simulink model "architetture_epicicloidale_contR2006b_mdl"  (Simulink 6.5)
settings: Solver=ode45  StartTime=0.0  StopTime=3  RelTol=1e-3
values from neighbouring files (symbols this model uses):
  al = Tipo(2)    [Flusso_Rotorico_An.m]
  b_c = kb*J_c    (= 4.94590955184)    [architetture_epicicloidale.m]    (also in architetture_epicicloidale_cont.m; architetture_epicicloidale_HEV.m = 92.8974810391; architetture_epicicloidale_prova.m; architetture_HEV_controllo.m = 9.28974810391)
  b_r = kb*J_r    (= 218.026030555)    [architetture_epicicloidale.m]    (also in architetture_epicicloidale_cont.m; architetture_epicicloidale_HEV.m; architetture_epicicloidale_prova.m; architetture_HEV_controllo.m = 21.8026030555)
  b_s = kb*J_s    (= 8.12277148259)    [architetture_epicicloidale.m]    (also in architetture_epicicloidale_cont.m; architetture_epicicloidale_HEV.m = 4.94590955184; architetture_epicicloidale_prova.m; architetture_HEV_controllo.m = 0.494590955184)
  b_sc = kb*J_sc    (= 92.8974810391)    [architetture_epicicloidale.m]    (also in architetture_epicicloidale_cont.m; architetture_epicicloidale_prova.m; epicicloidale.m; epicicloidale_da_solo.m)
  bm = 0.8*N*metri*secondo/rad    (= 0.8)    [architetture_epicicloidale.m]    (also in architetture_epicicloidale_cont.m; architetture_epicicloidale_HEV.m; architetture_epicicloidale_prova.m; architetture_HEV_controllo.m)
  d_cs = d0    (= 10)    [architetture_epicicloidale.m]    (also in architetture_epicicloidale_cont.m; architetture_epicicloidale_prova.m; epicicloidale.m; epicicloidale_da_solo.m)
  d_sr = d0    (= 10)    [architetture_epicicloidale.m]    (also in architetture_epicicloidale_cont.m; architetture_epicicloidale_prova.m; epicicloidale.m; epicicloidale_da_solo.m)
  I_m = eye(m-1)    [architetture_epicicloidale.m]    (also in architetture_epicicloidale_cont.m; architetture_epicicloidale_HEV.m; architetture_epicicloidale_prova.m; architetture_HEV_controllo.m)
  Iw0 = 0*wI0    [architetture_epicicloidale.m]    (also in architetture_epicicloidale_cont.m = wI0; architetture_epicicloidale_HEV.m; architetture_epicicloidale_prova.m; architetture_HEV_controllo.m)
  J_c = 1.3*0.5*pi*rho_acc*hc*r_c^4    (= 0.0494590955184)    [architetture_epicicloidale.m]    (also in architetture_epicicloidale_cont.m; architetture_epicicloidale_HEV.m = 0.928974810391; architetture_epicicloidale_prova.m; architetture_HEV_controllo.m = 0.928974810391)
  J_r = 0.5*pi*rho_acc*(hr*r_ri^4 + h_ring*(r_re^4-r_ri^4))    (= 2.18026030555)    [architetture_epicicloidale.m]    (also in architetture_epicicloidale_cont.m; architetture_epicicloidale_HEV.m; architetture_epicicloidale_prova.m; architetture_HEV_controllo.m)
  J_s = Nr_sat*0.5*pi*rho_acc*(hs*r_s^4 + hc*r_s^4)    (= 0.0812277148259)    [architetture_epicicloidale.m]    (also in architetture_epicicloidale_cont.m; architetture_epicicloidale_HEV.m = 0.0494590955184; architetture_epicicloidale_prova.m; architetture_HEV_controllo.m = 0.0494590955184)
  J_sc = Nr_sat*(r_c+r_s)^2*rho_acc*pi*(hs*r_s^2 + hc*r_s^2)    (= 0.928974810391)    [architetture_epicicloidale.m]    (also in architetture_epicicloidale_cont.m; architetture_epicicloidale_prova.m; epicicloidale.m; epicicloidale_da_solo.m)
  Jm = 1.6*kg*metri^2    (= 1.6)    [architetture_epicicloidale.m]    (also in architetture_epicicloidale_cont.m; architetture_epicicloidale_HEV.m = 1.64945909552; architetture_epicicloidale_prova.m; architetture_HEV_controllo.m = 0.529459095518)
  Jr = Jr([1:m-1],[1:m-1])    [architetture_epicicloidale.m]    (also in architetture_epicicloidale_cont.m; architetture_epicicloidale_HEV.m; architetture_epicicloidale_prova.m; architetture_HEV_controllo.m)
  K_cs = K0    (= 10000000)    [architetture_epicicloidale.m]    (also in architetture_epicicloidale_cont.m; architetture_epicicloidale_prova.m; epicicloidale.m; epicicloidale_da_solo.m)
  K_sr = K0    (= 10000000)    [architetture_epicicloidale.m]    (also in architetture_epicicloidale_cont.m; architetture_epicicloidale_prova.m; epicicloidale.m; epicicloidale_da_solo.m)
  Kf = diag(diag(MLb)'./fliplr(tau_m(1:m-1)))    [architetture_epicicloidale_cont.m]    (also in architetture_epicicloidale_HEV.m; architetture_epicicloidale_prova.m; architetture_HEV_controllo.m; architetture_HEV_startstop.m)
  Kr = Kr([1:m-1])    [architetture_epicicloidale.m]    (also in architetture_epicicloidale_cont.m; architetture_epicicloidale_HEV.m; architetture_epicicloidale_prova.m; architetture_HEV_controllo.m)
  Li = 0.1*Henry    (= 0.1)    [architetture_epicicloidale.m]    (also in architetture_epicicloidale_cont.m; architetture_epicicloidale_HEV.m; architetture_epicicloidale_prova.m; architetture_HEV_controllo.m)
  m = 5    [architetture_epicicloidale.m]    (also in architetture_epicicloidale_cont.m; architetture_epicicloidale_HEV.m; architetture_epicicloidale_prova.m; architetture_HEV_controllo.m)
  Mi = 0.08*Henry    (= 0.08)    [architetture_epicicloidale.m]    (also in architetture_epicicloidale_cont.m; architetture_epicicloidale_HEV.m; architetture_epicicloidale_prova.m; architetture_HEV_controllo.m)
  MKr = MKr([1:m-1],[1:m-1])    [architetture_epicicloidale.m]    (also in architetture_epicicloidale_cont.m; architetture_epicicloidale_HEV.m; architetture_epicicloidale_prova.m; architetture_HEV_controllo.m)
  MLb = MLb([1:m-1],[1:m-1])    [architetture_epicicloidale.m]    (also in architetture_epicicloidale_cont.m; architetture_epicicloidale_HEV.m; architetture_epicicloidale_prova.m; architetture_HEV_controllo.m)
  MR = MR([1:m-1],[1:m-1])    [architetture_epicicloidale.m]    (also in architetture_epicicloidale_cont.m; architetture_epicicloidale_HEV.m; architetture_epicicloidale_prova.m; architetture_HEV_controllo.m)
  Nar = 200    [architetture_epicicloidale.m]    (also in architetture_epicicloidale_cont.m; architetture_epicicloidale_HEV.m; architetture_epicicloidale_prova.m; architetture_HEV_controllo.m)
  Nc = 30    [architetture_epicicloidale.m]    (also in architetture_epicicloidale_cont.m; architetture_epicicloidale_HEV.m; architetture_epicicloidale_prova.m; architetture_HEV_controllo.m)
  Nr_sat = 4    [architetture_epicicloidale.m]    (also in architetture_epicicloidale_cont.m; architetture_epicicloidale_HEV.m; architetture_epicicloidale_prova.m; architetture_HEV_controllo.m)
  p = 1    [architetture_epicicloidale.m]    (also in architetture_epicicloidale_cont.m; architetture_epicicloidale_HEV.m; architetture_epicicloidale_prova.m; architetture_HEV_controllo.m)
  Phir = 0.02*Weber    (= 0.02)    [architetture_epicicloidale.m]    (also in architetture_epicicloidale_cont.m; architetture_epicicloidale_HEV.m; architetture_epicicloidale_prova.m; architetture_HEV_controllo.m)
  r_c = r_ri-2*r_s    (= 0.101859163579)    [architetture_epicicloidale.m]    (also in architetture_epicicloidale_cont.m; architetture_epicicloidale_prova.m; epicicloidale.m; epicicloidale_da_solo.m)
  r_ri = xds*Nr/(2*pi)    (= 0.248281711223)    [architetture_epicicloidale.m]    (also in architetture_epicicloidale_cont.m; architetture_epicicloidale_prova.m; epicicloidale.m; epicicloidale_da_solo.m)
  r_s = xds*Ns/(2*pi)    (= 0.0732112738223)    [architetture_epicicloidale.m]    (also in architetture_epicicloidale_cont.m; architetture_epicicloidale_HEV.m = 0.101859163579; architetture_epicicloidale_prova.m; architetture_HEV_controllo.m = 0.101859163579)
  Ri = 3*Ohm    (= 3)    [architetture_epicicloidale.m]    (also in architetture_epicicloidale_cont.m; architetture_epicicloidale_HEV.m; architetture_epicicloidale_prova.m; architetture_HEV_controllo.m = 0.1)
  Star = Si    [architetture_epicicloidale.m]    (also in architetture_epicicloidale_cont.m; architetture_epicicloidale_HEV.m; architetture_epicicloidale_prova.m; architetture_HEV_controllo.m)
  Tau_sc = 200*N*metri    (= 200)    [architetture_epicicloidale.m]    (also in architetture_epicicloidale_cont.m = 50; architetture_epicicloidale_prova.m = 50; epicicloidale.m = 4; epicicloidale_da_solo.m = 4)
  Tc = 0.05*ms    (= 5e-05)    [architetture_epicicloidale.m]    (also in architetture_epicicloidale_cont.m; architetture_epicicloidale_HEV.m; architetture_epicicloidale_prova.m; architetture_HEV_controllo.m)
  Thm0 = 0    [architetture_epicicloidale.m]    (also in architetture_epicicloidale_cont.m; architetture_epicicloidale_HEV.m; architetture_epicicloidale_prova.m; architetture_HEV_controllo.m)
  Tipo = eval(Flusso(ij).Tipo)    [architetture_epicicloidale.m]    (also in architetture_epicicloidale_cont.m; architetture_epicicloidale_HEV.m; architetture_epicicloidale_prova.m; architetture_HEV_controllo.m)
  tTb = tTb(:,[1:m-1])    [architetture_epicicloidale.m]    (also in architetture_epicicloidale_cont.m; architetture_epicicloidale_HEV.m; architetture_epicicloidale_prova.m; architetture_HEV_controllo.m)
  Wc_0 = 0*0.1*rad/secondo    (= 0)    [architetture_epicicloidale.m]    (also in architetture_epicicloidale_cont.m; architetture_epicicloidale_HEV.m; architetture_epicicloidale_prova.m; Confronto_CVT_EMR.m)
  Wm0 = 0*Wr_d    (= 0)    [architetture_epicicloidale.m]    (also in architetture_epicicloidale_cont.m = 62.5; architetture_epicicloidale_HEV.m; architetture_epicicloidale_prova.m; architetture_HEV_controllo.m)
  Wr_0 = Sys1.C(3,:)*[Wc_0; Wsc_0]    [architetture_epicicloidale.m]    (also in Confronto_CVT_EMR.m = 0; epicicloidale.m; epicicloidale_confronto_statico_elastico.m = [-r_s/r_r, 1+r_s/r_r]*[Ws_0; Wc_0]; epicicloidale_da_solo.m = [ -1/r_ri*r_c, (r_c+r_ri)/r_ri]*[Wc_0; Wsc_0])
  Wsc_0 = -0*0.2*rad/secondo    (= 0)    [architetture_epicicloidale.m]    (also in architetture_epicicloidale_cont.m; architetture_epicicloidale_HEV.m; architetture_epicicloidale_prova.m; epicicloidale.m = -0.2)
undefined symbols (not defined in the file or in its folder): a_0, a_1, B_Pneumatico, DFKc_max, eps_sk, K_Pneumatico, Lambda_mu, Mass_Matrix, Massa_Corpo_Auto, Mu_lambda, Raggio_Ruota_Ant, Raggio_Ruota_Pos, Sinusoidal, T_omega, tau_a0
libraries: simulink x13, dspmtrx3 x4, Tire_Soil x1
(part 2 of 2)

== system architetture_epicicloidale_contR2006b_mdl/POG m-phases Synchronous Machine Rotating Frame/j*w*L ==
  In1 : Inport  OutDataType=sfix(16)  OutScaling=2^0
  Gain1 : Gain  Gain=Kr  Multiplication=Matrix(K*u) (u vector)  ParameterDataType=sfix(16)  ParameterScaling=2^0  OutDataType=sfix(16)  OutScaling=2^0
  Gain2 : Gain  Gain=Jr  Multiplication=Matrix(K*u) (u vector)  ParameterDataType=sfix(16)  ParameterScaling=2^0  OutDataType=sfix(16)  OutScaling=2^0
  Gain4 : Gain  Gain=MLb  Multiplication=Matrix(K*u) (u vector)  ParameterDataType=sfix(16)  ParameterScaling=2^0  OutDataType=sfix(16)  OutScaling=2^0
  Product : Product  OutDataType=sfix(16)  OutScaling=2^0
  Out1 : Outport  OutDataType=sfix(16)  OutScaling=2^0
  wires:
  In1/1 -> Gain4/1
  [w_e] -> Gain1/1
  Gain1/1 -> Product/1
  Gain4/1 -> Product/2
  Product/1 -> Gain2/1
  Gain2/1 -> Out1/1

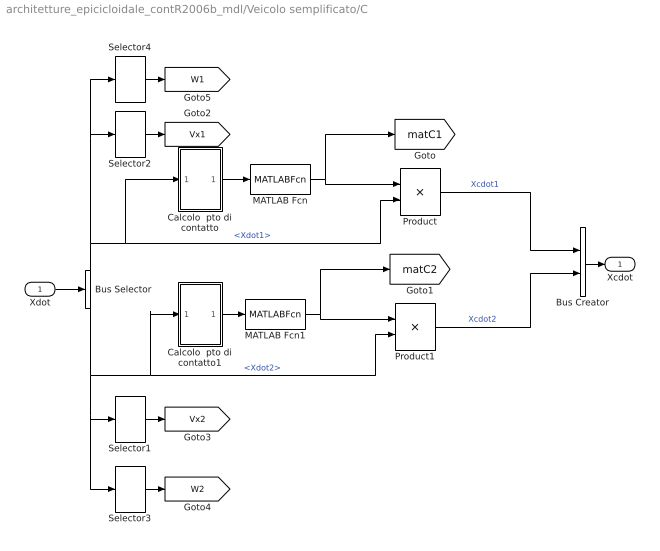
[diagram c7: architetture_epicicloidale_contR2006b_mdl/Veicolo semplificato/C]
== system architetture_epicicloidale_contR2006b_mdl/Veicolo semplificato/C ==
  Xdot : Inport  OutDataType=sfix(16)  OutScaling=2^0
  Bus Creator : BusCreator  Inputs=2
  Bus Selector : BusSelector  OutputSignals=Xdot1,Xdot2
  Calcolo  pto di contatto : Subsystem
  Calcolo  pto di contatto1 : Subsystem
  MATLAB Fcn : MATLABFcn  MATLABFcn=matrice_c  Output1D=off
  MATLAB Fcn1 : MATLABFcn  MATLABFcn=matrice_c  Output1D=off
  Product : Product  Inputs=**  Multiplication=Matrix(*)  OutDataType=sfix(16)  OutScaling=2^0
  Product1 : Product  Inputs=**  Multiplication=Matrix(*)  OutDataType=sfix(16)  OutScaling=2^0
  Selector1 : Selector  InputPortWidth=3  InputType=Vector  ElementSrc=Internal  Elements=1  RowSrc=Internal  Rows=1  ColumnSrc=Internal  Columns=1  IndexIsStartValue=off  OutputPortSize=[(-2)]
  Selector2 : Selector  InputPortWidth=3  InputType=Vector  ElementSrc=Internal  Elements=1  RowSrc=Internal  Rows=1  ColumnSrc=Internal  Columns=1  IndexIsStartValue=off  OutputPortSize=[(-2)]
  Selector3 : Selector  InputPortWidth=3  InputType=Vector  ElementSrc=Internal  Elements=3  RowSrc=Internal  Rows=3  ColumnSrc=Internal  Columns=1  IndexIsStartValue=off  OutputPortSize=[(-2)]
  Selector4 : Selector  InputPortWidth=3  InputType=Vector  ElementSrc=Internal  Elements=3  RowSrc=Internal  Rows=3  ColumnSrc=Internal  Columns=1  IndexIsStartValue=off  OutputPortSize=[(-2)]
  Xcdot : Outport  OutDataType=sfix(16)  OutScaling=2^0
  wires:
  Product/1 -> Bus Creator/1  "Xcdot1"
  MATLAB Fcn/1 -> Product/1, [matC1]
  Calcolo  pto di contatto/1(Out1) -> MATLAB Fcn/1
  Product1/1 -> Bus Creator/2  "Xcdot2"
  Bus Selector/2 -> Product1/2, Calcolo  pto di contatto1/1(In1), Selector1/1, Selector3/1  "<Xdot2>"
  MATLAB Fcn1/1 -> Product1/1, [matC2]
  Calcolo  pto di contatto1/1(Out1) -> MATLAB Fcn1/1
  Xdot/1 -> Bus Selector/1
  Bus Selector/1 -> Calcolo  pto di contatto/1(In1), Product/2, Selector2/1, Selector4/1  "<Xdot1>"
  Bus Creator/1 -> Xcdot/1
  Selector2/1 -> [Vx1]
  Selector1/1 -> [Vx2]
  Selector4/1 -> [W1]
  Selector3/1 -> [W2]

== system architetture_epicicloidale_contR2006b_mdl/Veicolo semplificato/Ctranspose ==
  Fc : Inport  OutDataType=sfix(16)  OutScaling=2^0
  Mux : Mux  Inputs=2
  Product : Product  Inputs=**  Multiplication=Matrix(*)  OutDataType=sfix(16)  OutScaling=2^0
  Product1 : Product  Inputs=**  Multiplication=Matrix(*)  OutDataType=sfix(16)  OutScaling=2^0
  Selector : Selector  InputPortWidth=6  InputType=Vector  ElementSrc=Internal  Elements=[1 2 3]  RowSrc=Internal  Rows=[1 2 3]  ColumnSrc=Internal  Columns=1  IndexIsStartValue=off  OutputPortSize=[(-2)]
  Selector1 : Selector  InputPortWidth=6  InputType=Vector  ElementSrc=Internal  Elements=[4 5 6]  RowSrc=Internal  Rows=[4 5 6]  ColumnSrc=Internal  Columns=1  IndexIsStartValue=off  OutputPortSize=[(-2)]
  Transpose : dspmtrx3/Transpose  SystemSampleTime=-1  Hermitian=off  overflowFlag=on
  Transpose1 : dspmtrx3/Transpose  SystemSampleTime=-1  Hermitian=off  overflowFlag=on
  F : Outport  OutDataType=sfix(16)  OutScaling=2^0
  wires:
  Transpose/1 -> Product/1
  [matC1] -> Transpose/1
  Transpose1/1 -> Product1/1
  [matC2] -> Transpose1/1
  Product/1 -> Mux/1
  Product1/1 -> Mux/2
  Mux/1 -> F/1
  Fc/1 -> Selector/1, Selector1/1
  Selector/1 -> Product/2
  Selector1/1 -> Product1/2

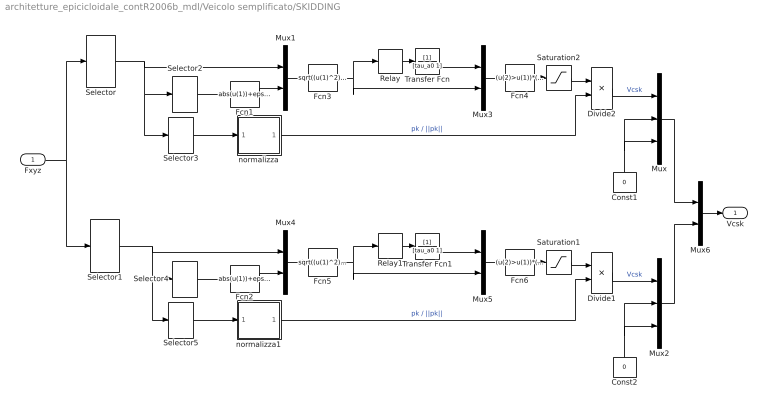
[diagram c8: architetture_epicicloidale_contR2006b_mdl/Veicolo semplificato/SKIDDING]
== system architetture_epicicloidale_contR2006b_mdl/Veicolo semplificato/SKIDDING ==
  Fxyz : Inport  OutDataType=sfix(16)  OutScaling=2^0
  Const1 : Constant  Orientation=up  Value=0  OutDataType=sfix(16)  OutScaling=2^0
  Const2 : Constant  Orientation=up  Value=0  OutDataType=sfix(16)  OutScaling=2^0
  Divide1 : Product  Inputs=**  OutDataType=sfix(16)  OutScaling=2^-10
  Divide2 : Product  Inputs=**  OutDataType=sfix(16)  OutScaling=2^-10
  Fcn1 : Fcn  Expr=abs(u(1))+eps_sk
  Fcn2 : Fcn  Expr=abs(u(1))+eps_sk
  Fcn3 : Fcn  Expr=sqrt((u(1)^2))/u(4)
  Fcn4 : Fcn  Expr=(u(2)>u(1))*(u(2)-u(1))^2*Kc
  Fcn5 : Fcn  Expr=sqrt((u(1)^2))/u(4)
  Fcn6 : Fcn  Expr=(u(2)>u(1))*(u(2)-u(1))^2*Kc
  Mux : Mux  Inputs=3
  Mux{1,3..6} (5 alike) : Mux  Inputs=2
  Mux2 : Mux  Inputs=3
  Relay : Relay  OnSwitchValue=a_0  OffSwitchValue=a_1  OnOutputValue=a_1  OffOutputValue=a_0  OutDataType=sfix(16)  OutScaling=2^0
  Relay1 : Relay  OnSwitchValue=a_0  OffSwitchValue=a_1  OnOutputValue=a_1  OffOutputValue=a_0  OutDataType=sfix(16)  OutScaling=2^0
  Saturation1 : Saturate  UpperLimit=DFKc_max  LowerLimit=0
  Saturation2 : Saturate  UpperLimit=DFKc_max  LowerLimit=0
  Selector : Selector  InputPortWidth=6  InputType=Vector  ElementSrc=Internal  Elements=[1 2 3]  RowSrc=Internal  Rows=[1 2 3]  ColumnSrc=Internal  Columns=1  IndexIsStartValue=off  OutputPortSize=[(-2)]
  Selector1 : Selector  InputPortWidth=6  InputType=Vector  ElementSrc=Internal  Elements=[4 5 6]  RowSrc=Internal  Rows=[4 5 6]  ColumnSrc=Internal  Columns=1  IndexIsStartValue=off  OutputPortSize=[(-2)]
  Selector2 : Selector  InputPortWidth=3  InputType=Vector  ElementSrc=Internal  Elements=[2]  RowSrc=Internal  Rows=[2]  ColumnSrc=Internal  Columns=1  IndexIsStartValue=off  OutputPortSize=[(-2)]
  Selector3 : Selector  InputPortWidth=3  InputType=Vector  ElementSrc=Internal  Elements=1  RowSrc=Internal  Rows=1  ColumnSrc=Internal  Columns=1  IndexIsStartValue=off  OutputPortSize=[(-2)]
  Selector4 : Selector  InputPortWidth=3  InputType=Vector  ElementSrc=Internal  Elements=[2]  RowSrc=Internal  Rows=[2]  ColumnSrc=Internal  Columns=1  IndexIsStartValue=off  OutputPortSize=[(-2)]
  Selector5 : Selector  InputPortWidth=3  InputType=Vector  ElementSrc=Internal  Elements=1  RowSrc=Internal  Rows=1  ColumnSrc=Internal  Columns=1  IndexIsStartValue=off  OutputPortSize=[(-2)]
  Transfer Fcn : TransferFcn  Denominator=[tau_a0 1]
  Transfer Fcn1 : TransferFcn  Denominator=[tau_a0 1]
  normalizza : Subsystem
  normalizza1 : Subsystem
  Vcsk : Outport  OutDataType=sfix(16)  OutScaling=2^0
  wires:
  Transfer Fcn/1 -> Mux3/1
  Relay/1 -> Transfer Fcn/1
  Mux3/1 -> Fcn4/1
  Fcn1/1 -> Mux1/2
  Mux1/1 -> Fcn3/1
  Fcn3/1 -> Mux3/2, Relay/1
  Fcn4/1 -> Saturation2/1
  Saturation2/1 -> Divide2/1
  normalizza/1(Out1) -> Divide2/2  "pk / ||pk||"
  Selector3/1 -> normalizza/1(In1)
  Selector2/1 -> Fcn1/1
  Fxyz/1 -> Selector/1, Selector1/1
  Divide2/1 -> Mux/1  "Vcsk"
  Selector/1 -> Selector2/1, Selector3/1, Mux1/1
  Const1/1 -> Mux/2, Mux/3
  Transfer Fcn1/1 -> Mux5/1
  Relay1/1 -> Transfer Fcn1/1
  Mux5/1 -> Fcn6/1
  Fcn2/1 -> Mux4/2
  Mux4/1 -> Fcn5/1
  Fcn5/1 -> Mux5/2, Relay1/1
  Fcn6/1 -> Saturation1/1
  Saturation1/1 -> Divide1/1
  normalizza1/1(Out1) -> Divide1/2  "pk / ||pk||"
  Selector5/1 -> normalizza1/1(In1)
  Selector4/1 -> Fcn2/1
  Divide1/1 -> Mux2/1  "Vcsk"
  Selector1/1 -> Selector4/1, Selector5/1, Mux4/1
  Const2/1 -> Mux2/2, Mux2/3
  Mux/1 -> Mux6/1
  Mux2/1 -> Mux6/2
  Mux6/1 -> Vcsk/1

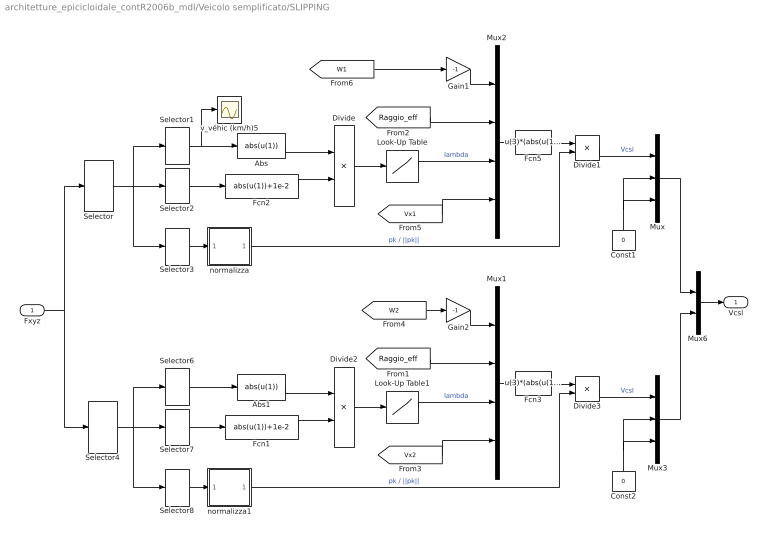
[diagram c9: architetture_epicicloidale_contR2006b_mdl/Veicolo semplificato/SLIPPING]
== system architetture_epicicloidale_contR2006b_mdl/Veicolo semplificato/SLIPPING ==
  Fxyz : Inport  OutDataType=sfix(16)  OutScaling=2^0
  Abs : Fcn  Expr=abs(u(1))
  Abs1 : Fcn  Expr=abs(u(1))
  Const1 : Constant  Orientation=up  Value=0  OutDataType=sfix(16)  OutScaling=2^0
  Const2 : Constant  Orientation=up  Value=0  OutDataType=sfix(16)  OutScaling=2^0
  Divide : Product  Inputs=*/  OutDataType=sfix(16)  OutScaling=2^-10
  Divide1 : Product  Inputs=**  OutDataType=sfix(16)  OutScaling=2^-10
  Divide2 : Product  Inputs=*/  OutDataType=sfix(16)  OutScaling=2^-10
  Divide3 : Product  Inputs=**  OutDataType=sfix(16)  OutScaling=2^-10
  Fcn1 : Fcn  Expr=abs(u(1))+1e-2
  Fcn2 : Fcn  Expr=abs(u(1))+1e-2
  Fcn3 : Fcn  Expr=u(3)*(abs(u(1)*u(2))*(abs(u(1)*u(2))<=abs(u(4)))+abs(u(4))*(abs(u(1)*u(2))>abs(u(4))))
  Fcn5 : Fcn  Expr=u(3)*(abs(u(1)*u(2))*(abs(u(1)*u(2))<=abs(u(4)))+abs(u(4))*(abs(u(1)*u(2))>abs(u(4))))
  Gain1 : Gain  Gain=-1  ParameterDataType=sfix(16)  ParameterScaling=2^0  OutDataType=sfix(16)  OutScaling=2^0
  Gain2 : Gain  Gain=-1  ParameterDataType=sfix(16)  ParameterScaling=2^0  OutDataType=sfix(16)  OutScaling=2^0
  Look-Up Table : Lookup  InputValues=Mu_lambda  OutputValues=Lambda_mu  OutDataType=sfix(16)  OutScaling=2^0
  Look-Up Table1 : Lookup  InputValues=Mu_lambda  OutputValues=Lambda_mu  OutDataType=sfix(16)  OutScaling=2^0
  Mux : Mux  Inputs=3
  Mux1 : Mux
  Mux2 : Mux
  Mux3 : Mux  Inputs=3
  Mux6 : Mux  Inputs=2
  Selector : Selector  InputPortWidth=6  InputType=Vector  ElementSrc=Internal  Elements=[1 2 3]  RowSrc=Internal  Rows=[1 2 3]  ColumnSrc=Internal  Columns=1  IndexIsStartValue=off  OutputPortSize=[(-2)]
  Selector{1,3,6,8} (4 alike) : Selector  InputPortWidth=3  InputType=Vector  ElementSrc=Internal  Elements=1  RowSrc=Internal  Rows=1  ColumnSrc=Internal  Columns=1  IndexIsStartValue=off  OutputPortSize=[(-2)]
  Selector2 : Selector  InputPortWidth=3  InputType=Vector  ElementSrc=Internal  Elements=[2]  RowSrc=Internal  Rows=[2]  ColumnSrc=Internal  Columns=1  IndexIsStartValue=off  OutputPortSize=[(-2)]
  Selector4 : Selector  InputPortWidth=6  InputType=Vector  ElementSrc=Internal  Elements=[4 5 6]  RowSrc=Internal  Rows=[4 5 6]  ColumnSrc=Internal  Columns=1  IndexIsStartValue=off  OutputPortSize=[(-2)]
  Selector7 : Selector  InputPortWidth=3  InputType=Vector  ElementSrc=Internal  Elements=[2]  RowSrc=Internal  Rows=[2]  ColumnSrc=Internal  Columns=1  IndexIsStartValue=off  OutputPortSize=[(-2)]
  normalizza : Subsystem
  normalizza1 : Subsystem
  v_véhic (km/h)5 : Scope
  Vcsl : Outport  OutDataType=sfix(16)  OutScaling=2^0
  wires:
  Fcn5/1 -> Divide1/1
  Mux2/1 -> Fcn5/1
  [Vx1] -> Mux2/4
  Gain1/1 -> Mux2/1
  [Raggio_eff] -> Mux2/2
  Divide/1 -> Look-Up Table/1
  Look-Up Table/1 -> Mux2/3  "lambda"
  Selector1/1 -> Abs/1, v_véhic (km/h)5/1
  Abs/1 -> Divide/1
  Fcn2/1 -> Divide/2
  Selector3/1 -> normalizza/1(In1)
  Selector2/1 -> Fcn2/1
  Selector/1 -> Selector2/1, Selector3/1, Selector1/1
  normalizza/1(Out1) -> Divide1/2  "pk / ||pk||"
  Fxyz/1 -> Selector/1, Selector4/1
  Fcn3/1 -> Divide3/1
  Mux1/1 -> Fcn3/1
  [Vx2] -> Mux1/4
  Gain2/1 -> Mux1/1
  [Raggio_eff] -> Mux1/2
  Divide2/1 -> Look-Up Table1/1
  Look-Up Table1/1 -> Mux1/3  "lambda"
  Selector6/1 -> Abs1/1
  Abs1/1 -> Divide2/1
  Fcn1/1 -> Divide2/2
  Selector8/1 -> normalizza1/1(In1)
  Selector7/1 -> Fcn1/1
  Selector4/1 -> Selector7/1, Selector8/1, Selector6/1
  normalizza1/1(Out1) -> Divide3/2  "pk / ||pk||"
  Divide1/1 -> Mux/1  "Vcsl"
  Const1/1 -> Mux/3, Mux/2
  Divide3/1 -> Mux3/1  "Vcsl"
  Const2/1 -> Mux3/2, Mux3/3
  Mux/1 -> Mux6/1
  Mux3/1 -> Mux6/2
  Mux6/1 -> Vcsl/1
  [W1] -> Gain1/1
  [W2] -> Gain2/1

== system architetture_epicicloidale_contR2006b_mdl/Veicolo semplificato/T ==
  V : Inport  OutDataType=sfix(16)  OutScaling=2^0
  Bus Creator : BusCreator  Inputs=2
  MATLAB Fcn : MATLABFcn  MATLABFcn=matrice_T  Output1D=off
  Product : Product  Inputs=**  Multiplication=Matrix(*)  OutDataType=sfix(16)  OutScaling=2^0
  Selector : Selector  InputPortWidth=6  InputType=Vector  ElementSrc=Internal  Elements=[1 2 3]  RowSrc=Internal  Rows=[1 2 3]  ColumnSrc=Internal  Columns=1  IndexIsStartValue=off  OutputPortSize=[(-2)]
  Selector1 : Selector  InputPortWidth=6  InputType=Vector  ElementSrc=Internal  Elements=[4 5 6]  RowSrc=Internal  Rows=[4 5 6]  ColumnSrc=Internal  Columns=1  IndexIsStartValue=off  OutputPortSize=[(-2)]
  Xdot : Outport  OutDataType=sfix(16)  OutScaling=2^0
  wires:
  [thetaM] -> MATLAB Fcn/1
  V/1 -> Product/2
  MATLAB Fcn/1 -> Product/1, [matT]
  Product/1 -> Selector/1, Selector1/1
  Selector1/1 -> Bus Creator/2  "Xdot2"
  Selector/1 -> Bus Creator/1  "Xdot1"
  Bus Creator/1 -> Xdot/1

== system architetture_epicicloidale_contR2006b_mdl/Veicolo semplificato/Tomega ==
  V : Inport  OutDataType=sfix(16)  OutScaling=2^0
  Constant5 : Constant  Value=T_omega  OutDataType=sfix(16)  OutScaling=2^0
  Product : Product  Inputs=**  Multiplication=Matrix(*)  OutDataType=sfix(16)  OutScaling=2^0
  Vt : Outport  OutDataType=sfix(16)  OutScaling=2^0
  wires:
  Constant5/1 -> Product/1
  V/1 -> Product/2
  Product/1 -> Vt/1

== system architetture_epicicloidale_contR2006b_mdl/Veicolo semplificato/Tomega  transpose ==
  T : Inport  OutDataType=sfix(16)  OutScaling=2^0
  Constant5 : Constant  Value=T_omega  OutDataType=sfix(16)  OutScaling=2^0
  Product : Product  Inputs=**  Multiplication=Matrix(*)  OutDataType=sfix(16)  OutScaling=2^0
  Transpose : dspmtrx3/Transpose  SystemSampleTime=-1  Hermitian=off  overflowFlag=on
  Tt : Outport  OutDataType=sfix(16)  OutScaling=2^0
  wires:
  Product/1 -> Tt/1
  T/1 -> Product/2
  Constant5/1 -> Transpose/1
  Transpose/1 -> Product/1

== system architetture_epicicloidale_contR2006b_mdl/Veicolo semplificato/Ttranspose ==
  F : Inport  OutDataType=sfix(16)  OutScaling=2^0
  Product : Product  Inputs=**  Multiplication=Matrix(*)  OutDataType=sfix(16)  OutScaling=2^0
  Transpose : dspmtrx3/Transpose  SystemSampleTime=-1  Hermitian=off  overflowFlag=on
  Ft : Outport  OutDataType=sfix(16)  OutScaling=2^0
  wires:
  Product/1 -> Ft/1
  F/1 -> Product/2
  [matT] -> Transpose/1
  Transpose/1 -> Product/1

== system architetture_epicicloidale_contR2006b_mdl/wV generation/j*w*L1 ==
  In1 : Inport  OutDataType=sfix(16)  OutScaling=2^0
  In2 : Inport  Port=2  OutDataType=sfix(16)  OutScaling=2^0
  Gain1 : Gain  Gain=Kr  Multiplication=Matrix(K*u) (u vector)  ParameterDataType=sfix(16)  ParameterScaling=2^0  OutDataType=sfix(16)  OutScaling=2^0
  Gain2 : Gain  Gain=Jr  Multiplication=Matrix(K*u) (u vector)  ParameterDataType=sfix(16)  ParameterScaling=2^0  OutDataType=sfix(16)  OutScaling=2^0
  Gain4 : Gain  Gain=MLb  Multiplication=Matrix(K*u) (u vector)  ParameterDataType=sfix(16)  ParameterScaling=2^0  OutDataType=sfix(16)  OutScaling=2^0
  Product : Product  OutDataType=sfix(16)  OutScaling=2^0
  Out1 : Outport  OutDataType=sfix(16)  OutScaling=2^0
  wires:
  In1/1 -> Gain4/1
  In2/1 -> Gain1/1
  Gain1/1 -> Product/1
  Gain4/1 -> Product/2
  Product/1 -> Gain2/1
  Gain2/1 -> Out1/1

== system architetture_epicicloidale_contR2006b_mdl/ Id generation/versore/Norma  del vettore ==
  In1 : Inport  OutDataType=sfix(16)  OutScaling=2^0
  Dot Product : simulink/Math Operations/Dot Product  InputSameDT=on  OutDataType=sfix(16)  OutScaling=2^-10  DoSatur=off
  Math Function : Math  Operator=sqrt  OutDataType=sfix(16)  OutScaling=2^0
  Out1 : Outport  OutDataType=sfix(16)  OutScaling=2^0
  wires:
  Math Function/1 -> Out1/1
  Dot Product/1 -> Math Function/1
  In1/1 -> Dot Product/2, Dot Product/1

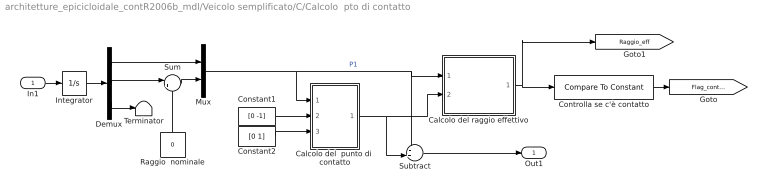
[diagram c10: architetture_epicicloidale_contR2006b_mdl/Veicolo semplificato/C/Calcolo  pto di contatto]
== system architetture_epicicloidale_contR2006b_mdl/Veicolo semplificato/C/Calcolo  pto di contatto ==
  In1 : Inport  OutDataType=sfix(16)  OutScaling=2^0
  Calcolo del  punto di  contatto : Subsystem  AncestorBlock=|
      | Tire_Soil/Tire-soil contact
      | ENERGETIC/Calcolo versori
      | e punto di contatto C/Subsystem2/Calcolo del 
      | punto di 
      | contatto
  Calcolo del raggio effettivo : Subsystem  AncestorBlock=|
      | Tire_Soil/Tire-soil contact
      | ENERGETIC/Calcolo versori
      | e punto di contatto C/Subsystem2/Calcolo del raggio
      | effettivo
  Constant1 : Constant  Value=[0 -1]  OutDataType=sfix(16)  OutScaling=2^0
  Constant2 : Constant  Value=[0 1]  OutDataType=sfix(16)  OutScaling=2^0
  Controlla se c'è contatto : simulink/Logic and Bit Operations/Compare To Constant  SystemSampleTime=-1  relop=<  const=Raggio_Ruota_Ant  LogicOutDataTypeMode=boolean  ZeroCross=off
  Demux : Demux  Outputs=3
  Integrator : Integrator  InitialCondition=[0 Raggio_Ruota_Pos 0]
  Mux : Mux  Inputs=2
  Raggio  nominale : Constant  Orientation=up  Value=0  OutDataType=sfix(16)  OutScaling=2^0
  Subtract : Sum  Inputs=-+|  OutDataType=sfix(16)  OutScaling=2^-10
  Sum : Sum  Inputs=|++  OutDataType=sfix(16)  OutScaling=2^0
  Terminator : Terminator
  Out1 : Outport  OutDataType=sfix(16)  OutScaling=2^0
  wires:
  Demux/3 -> Terminator/1
  Demux/2 -> Sum/1
  Raggio  nominale/1 -> Sum/2
  Demux/1 -> Mux/1
  Sum/1 -> Mux/2
  Integrator/1 -> Demux/1
  Constant2/1 -> Calcolo del  punto di  contatto/3(n)
  Subtract/1 -> Out1/1
  Calcolo del  punto di  contatto/1(Pc) -> Calcolo del raggio effettivo/2(Pc), Subtract/2
  Constant1/1 -> Calcolo del  punto di  contatto/2(r)
  Mux/1 -> Subtract/1, Calcolo del raggio effettivo/1(P1), Calcolo del  punto di  contatto/1(P1)  "P1"
  Calcolo del raggio effettivo/1("Raggio_eff ") -> Controlla se c'è contatto/1, [Raggio_eff]
  In1/1 -> Integrator/1
  Controlla se c'è contatto/1 -> [Flag_contatto]

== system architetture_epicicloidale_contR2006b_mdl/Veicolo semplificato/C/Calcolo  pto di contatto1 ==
  In1 : Inport  OutDataType=sfix(16)  OutScaling=2^0
  Calcolo del  punto di  contatto : Subsystem  AncestorBlock=|
      | Tire_Soil/Tire-soil contact
      | ENERGETIC/Calcolo versori
      | e punto di contatto C/Subsystem2/Calcolo del 
      | punto di 
      | contatto
  Calcolo del raggio effettivo : Tire_Soil/Tire-soil contact ENERGETIC/Calcolo versori e punto di contatto C/Subsystem2/Calcolo del raggio effettivo  SystemSampleTime=-1
  Constant1 : Constant  Value=[0 -1]  OutDataType=sfix(16)  OutScaling=2^0
  Constant2 : Constant  Value=[0 1]  OutDataType=sfix(16)  OutScaling=2^0
  Demux : Demux  Outputs=3
  Integrator : Integrator
  Mux : Mux  Inputs=2
  Raggio  nominale : Constant  Orientation=up  Value=Raggio_Ruota_Pos  OutDataType=sfix(16)  OutScaling=2^0
  Subtract : Sum  Inputs=-+|  OutDataType=sfix(16)  OutScaling=2^-10
  Sum : Sum  Inputs=|++  OutDataType=sfix(16)  OutScaling=2^0
  Terminator : Terminator
  Terminator2 : Terminator
  Out1 : Outport  OutDataType=sfix(16)  OutScaling=2^0
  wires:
  Demux/3 -> Terminator/1
  Demux/2 -> Sum/1
  Raggio  nominale/1 -> Sum/2
  Demux/1 -> Mux/1
  Sum/1 -> Mux/2
  Integrator/1 -> Demux/1
  Constant2/1 -> Calcolo del  punto di  contatto/3(n)
  Subtract/1 -> Out1/1
  Calcolo del  punto di  contatto/1(Pc) -> Subtract/2, Calcolo del raggio effettivo/2
  Constant1/1 -> Calcolo del  punto di  contatto/2(r)
  Mux/1 -> Subtract/1, Calcolo del raggio effettivo/1, Calcolo del  punto di  contatto/1(P1)  "P1"
  Calcolo del raggio effettivo/1 -> Terminator2/1
  In1/1 -> Integrator/1

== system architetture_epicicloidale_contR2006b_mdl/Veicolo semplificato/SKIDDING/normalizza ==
  In1 : Inport  OutDataType=sfix(16)  OutScaling=2^0
  Constant : Constant  Value=eps  OutDataType=sfix(16)  OutScaling=2^0
  Divide : Product  Inputs=*/  OutDataType=sfix(16)  OutScaling=2^-10
  Norma  del vettore : Subsystem
  Sum1 : Sum  Inputs=|++  OutDataType=sfix(16)  OutScaling=2^0
  Out1 : Outport  OutDataType=sfix(16)  OutScaling=2^0
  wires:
  Divide/1 -> Out1/1  "versore"
  Constant/1 -> Sum1/2
  Sum1/1 -> Divide/2
  Norma  del vettore/1(Out1) -> Sum1/1
  In1/1 -> Norma  del vettore/1(In1), Divide/1

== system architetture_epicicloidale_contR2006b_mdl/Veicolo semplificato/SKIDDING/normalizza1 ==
  In1 : Inport  OutDataType=sfix(16)  OutScaling=2^0
  Constant : Constant  Value=eps  OutDataType=sfix(16)  OutScaling=2^0
  Divide : Product  Inputs=*/  OutDataType=sfix(16)  OutScaling=2^-10
  Norma  del vettore : Subsystem
  Sum1 : Sum  Inputs=|++  OutDataType=sfix(16)  OutScaling=2^0
  Out1 : Outport  OutDataType=sfix(16)  OutScaling=2^0
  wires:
  Divide/1 -> Out1/1  "versore"
  Constant/1 -> Sum1/2
  Sum1/1 -> Divide/2
  Norma  del vettore/1(Out1) -> Sum1/1
  In1/1 -> Norma  del vettore/1(In1), Divide/1

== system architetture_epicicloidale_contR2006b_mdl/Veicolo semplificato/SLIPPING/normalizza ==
  In1 : Inport  OutDataType=sfix(16)  OutScaling=2^0
  Constant : Constant  Value=eps  OutDataType=sfix(16)  OutScaling=2^0
  Divide : Product  Inputs=*/  OutDataType=sfix(16)  OutScaling=2^-10
  Norma  del vettore : Subsystem
  Sum1 : Sum  Inputs=|++  OutDataType=sfix(16)  OutScaling=2^0
  Out1 : Outport  OutDataType=sfix(16)  OutScaling=2^0
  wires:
  Divide/1 -> Out1/1  "versore"
  Constant/1 -> Sum1/2
  Sum1/1 -> Divide/2
  Norma  del vettore/1(Out1) -> Sum1/1
  In1/1 -> Norma  del vettore/1(In1), Divide/1

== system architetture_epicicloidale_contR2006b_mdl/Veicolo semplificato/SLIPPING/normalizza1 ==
  In1 : Inport  OutDataType=sfix(16)  OutScaling=2^0
  Constant : Constant  Value=eps  OutDataType=sfix(16)  OutScaling=2^0
  Divide : Product  Inputs=*/  OutDataType=sfix(16)  OutScaling=2^-10
  Norma  del vettore : Subsystem
  Sum1 : Sum  Inputs=|++  OutDataType=sfix(16)  OutScaling=2^0
  Out1 : Outport  OutDataType=sfix(16)  OutScaling=2^0
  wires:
  Divide/1 -> Out1/1  "versore"
  Constant/1 -> Sum1/2
  Sum1/1 -> Divide/2
  Norma  del vettore/1(Out1) -> Sum1/1
  In1/1 -> Norma  del vettore/1(In1), Divide/1

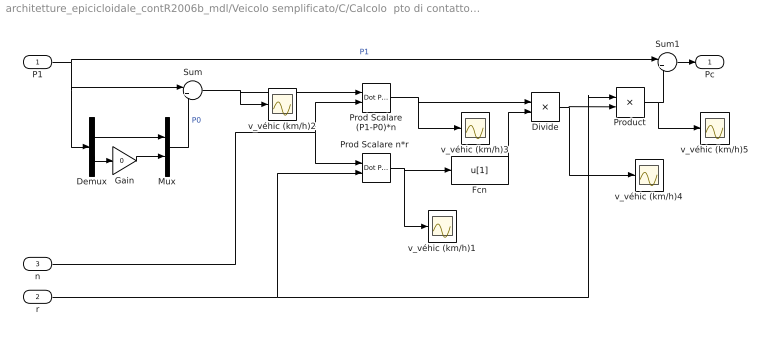
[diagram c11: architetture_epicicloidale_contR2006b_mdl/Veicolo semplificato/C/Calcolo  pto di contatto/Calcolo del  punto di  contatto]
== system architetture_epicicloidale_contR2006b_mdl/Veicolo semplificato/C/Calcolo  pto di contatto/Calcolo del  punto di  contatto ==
  P1 : Inport  OutDataType=sfix(16)  OutScaling=2^0
  r : Inport  Port=2  OutDataType=sfix(16)  OutScaling=2^0
  n : Inport  Port=3  OutDataType=sfix(16)  OutScaling=2^0
  Demux : Demux  Outputs=2
  Divide : Product  Inputs=*/  OutDataType=sfix(16)  OutScaling=2^-10
  Fcn : Fcn  Expr=u[1]
  Gain : Gain  Gain=0  ParameterDataType=sfix(16)  ParameterScaling=2^0  OutDataType=sfix(16)  OutScaling=2^0
  Mux : Mux  Inputs=2
  Prod Scalare (P1-P0)*n : simulink/Math Operations/Dot Product  InputSameDT=on  OutDataType=sfix(16)  OutScaling=2^-10  DoSatur=off
  "Prod Scalare n*r " : simulink/Math Operations/Dot Product  InputSameDT=on  OutDataType=sfix(16)  OutScaling=2^-10  DoSatur=off
  Product : Product  OutDataType=sfix(16)  OutScaling=2^0
  Sum : Sum  Inputs=|+-  OutDataType=sfix(16)  OutScaling=2^0
  Sum1 : Sum  Inputs=|+-  OutDataType=sfix(16)  OutScaling=2^0
  v_véhic (km/h){1..5} (5 alike) : Scope
  Pc : Outport  OutDataType=sfix(16)  OutScaling=2^0
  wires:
  n/1 -> Prod Scalare (P1-P0)*n/2, "Prod Scalare n*r "/1
  Fcn/1 -> Divide/2
  Sum/1 -> Prod Scalare (P1-P0)*n/1, v_véhic (km/h)2/1
  Sum1/1 -> Pc/1
  Product/1 -> Sum1/2, v_véhic (km/h)5/1
  Divide/1 -> Product/2, v_véhic (km/h)4/1
  "Prod Scalare n*r "/1 -> Fcn/1, v_véhic (km/h)1/1
  Prod Scalare (P1-P0)*n/1 -> Divide/1, v_véhic (km/h)3/1
  r/1 -> Product/1, "Prod Scalare n*r "/2
  P1/1 -> Sum1/1, Sum/1, Demux/1  "P1"
  Demux/2 -> Gain/1
  Demux/1 -> Mux/1
  Mux/1 -> Sum/2  "P0"
  Gain/1 -> Mux/2

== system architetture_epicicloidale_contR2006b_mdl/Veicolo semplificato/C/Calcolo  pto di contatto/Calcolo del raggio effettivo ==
  P1 : Inport  OutDataType=sfix(16)  OutScaling=2^0
  Pc : Inport  Port=2  OutDataType=sfix(16)  OutScaling=2^0
  Dot Product : simulink/Math Operations/Dot Product  InputSameDT=on  OutDataType=sfix(16)  OutScaling=2^-10  DoSatur=off
  Sqrt : Fcn  Expr=sqrt(u[1])
  Sum : Sum  Inputs=|+-  OutDataType=sfix(16)  OutScaling=2^0
  "Raggio_eff " : Outport  OutDataType=sfix(16)  OutScaling=2^0
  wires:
  Dot Product/1 -> Sqrt/1
  Sqrt/1 -> "Raggio_eff "/1
  Sum/1 -> Dot Product/2, Dot Product/1
  Pc/1 -> Sum/2
  P1/1 -> Sum/1

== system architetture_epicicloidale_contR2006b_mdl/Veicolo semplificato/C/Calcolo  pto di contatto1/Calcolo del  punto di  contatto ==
  P1 : Inport  OutDataType=sfix(16)  OutScaling=2^0
  r : Inport  Port=2  OutDataType=sfix(16)  OutScaling=2^0
  n : Inport  Port=3  OutDataType=sfix(16)  OutScaling=2^0
  Demux : Demux  Outputs=2
  Divide : Product  Inputs=*/  OutDataType=sfix(16)  OutScaling=2^-10
  Fcn : Fcn  Expr=u[1]+eps
  Gain : Gain  Gain=0  ParameterDataType=sfix(16)  ParameterScaling=2^0  OutDataType=sfix(16)  OutScaling=2^0
  Mux : Mux  Inputs=2
  Prod Scalare (P1-P0)*n : simulink/Math Operations/Dot Product  InputSameDT=on  OutDataType=sfix(16)  OutScaling=2^-10  DoSatur=off
  "Prod Scalare n*r " : simulink/Math Operations/Dot Product  InputSameDT=on  OutDataType=sfix(16)  OutScaling=2^-10  DoSatur=off
  Product : Product  OutDataType=sfix(16)  OutScaling=2^0
  Sum : Sum  Inputs=|+-  OutDataType=sfix(16)  OutScaling=2^0
  Sum1 : Sum  Inputs=|+-  OutDataType=sfix(16)  OutScaling=2^0
  Pc : Outport  OutDataType=sfix(16)  OutScaling=2^0
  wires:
  n/1 -> Prod Scalare (P1-P0)*n/2, "Prod Scalare n*r "/1
  Fcn/1 -> Divide/2
  Sum/1 -> Prod Scalare (P1-P0)*n/1
  Sum1/1 -> Pc/1
  Product/1 -> Sum1/2
  Divide/1 -> Product/2
  "Prod Scalare n*r "/1 -> Fcn/1
  Prod Scalare (P1-P0)*n/1 -> Divide/1
  r/1 -> Product/1, "Prod Scalare n*r "/2
  P1/1 -> Sum1/1, Sum/1, Demux/1  "P1"
  Demux/2 -> Gain/1
  Demux/1 -> Mux/1
  Mux/1 -> Sum/2  "P0"
  Gain/1 -> Mux/2

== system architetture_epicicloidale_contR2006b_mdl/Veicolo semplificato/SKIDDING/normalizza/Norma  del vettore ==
  In1 : Inport  OutDataType=sfix(16)  OutScaling=2^0
  Dot Product : simulink/Math Operations/Dot Product  InputSameDT=on  OutDataType=sfix(16)  OutScaling=2^-10  DoSatur=off
  Math Function : Math  Operator=sqrt  OutDataType=sfix(16)  OutScaling=2^0
  Out1 : Outport  OutDataType=sfix(16)  OutScaling=2^0
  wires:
  Math Function/1 -> Out1/1
  Dot Product/1 -> Math Function/1
  In1/1 -> Dot Product/2, Dot Product/1

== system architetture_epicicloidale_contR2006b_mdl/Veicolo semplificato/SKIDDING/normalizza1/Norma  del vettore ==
  In1 : Inport  OutDataType=sfix(16)  OutScaling=2^0
  Dot Product : simulink/Math Operations/Dot Product  InputSameDT=on  OutDataType=sfix(16)  OutScaling=2^-10  DoSatur=off
  Math Function : Math  Operator=sqrt  OutDataType=sfix(16)  OutScaling=2^0
  Out1 : Outport  OutDataType=sfix(16)  OutScaling=2^0
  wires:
  Math Function/1 -> Out1/1
  Dot Product/1 -> Math Function/1
  In1/1 -> Dot Product/2, Dot Product/1

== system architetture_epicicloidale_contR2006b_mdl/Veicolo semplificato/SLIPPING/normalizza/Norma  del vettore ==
  In1 : Inport  OutDataType=sfix(16)  OutScaling=2^0
  Dot Product : simulink/Math Operations/Dot Product  InputSameDT=on  OutDataType=sfix(16)  OutScaling=2^-10  DoSatur=off
  Math Function : Math  Operator=sqrt  OutDataType=sfix(16)  OutScaling=2^0
  Out1 : Outport  OutDataType=sfix(16)  OutScaling=2^0
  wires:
  Math Function/1 -> Out1/1
  Dot Product/1 -> Math Function/1
  In1/1 -> Dot Product/2, Dot Product/1

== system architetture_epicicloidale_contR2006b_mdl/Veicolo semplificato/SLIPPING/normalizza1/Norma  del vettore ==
  In1 : Inport  OutDataType=sfix(16)  OutScaling=2^0
  Dot Product : simulink/Math Operations/Dot Product  InputSameDT=on  OutDataType=sfix(16)  OutScaling=2^-10  DoSatur=off
  Math Function : Math  Operator=sqrt  OutDataType=sfix(16)  OutScaling=2^0
  Out1 : Outport  OutDataType=sfix(16)  OutScaling=2^0
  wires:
  Math Function/1 -> Out1/1
  Dot Product/1 -> Math Function/1
  In1/1 -> Dot Product/2, Dot Product/1
